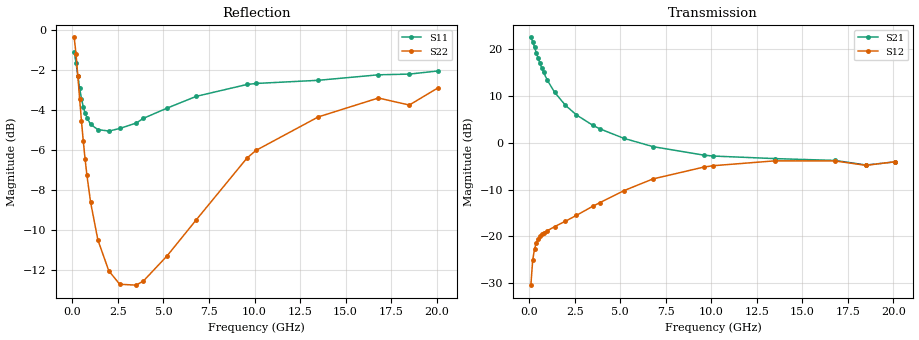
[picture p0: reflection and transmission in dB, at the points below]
!  Infineon Technologies AG
! BFR380L3 , PF131585-7, No.6, Th 09.10.01, soldered on pcb-board, measured with PP GSG850
!  Vce=2.0 V,  Ic=4.0 mA
! Common Emitter S-Parameters:  15. November 2001
#  GHz  S  MA  R  50
! f  S11  S21  S12  S22
! GHz  Mag  Ang  Mag  Ang  Mag  Ang  Mag  Ang
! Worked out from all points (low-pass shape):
!   201 points, 100 MHz to 20.1 GHz, reference 50 ohm
!   highest |S21| = 22.46 dB at 100 MHz (marker M1); lowest = -4.8 dB at 18.5 GHz (marker M2)
!   |S21| within 3 dB of the highest: start of sweep to 378.5 MHz
!   lowest |S11| = -5.1 dB at 2 GHz (marker M3), VSWR 3.53, Z = 14.2 + j0.206 ohm
!   |S11| at or under -10 dB: nowhere
!   |S22| runs from -12.9 to -0.4 dB; largest |S21 - S12| = 13
!   S11 on the Smith chart (normalised r, x): 100 MHz: 1.14, -3.99; 400 MHz: 0.34, -1.00; 1 GHz: 0.29, -0.31; 3.9 GHz: 0.28, +0.32; 9.6 GHz: 0.36, +1.11; 20.1 GHz: 0.98, +2.55
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0.1  0.8814 -26.2  13.27 162.5  0.03022 75.1  0.9583 -15.7
0.2  0.8274 -49.6  11.92 147.4  0.05574 64.3  0.8697 -29.3
0.3  0.7691 -70.4  10.47 135.0  0.0735 55.5  0.7655 -39.9
0.4  0.7137 -86.6  9.117 125.2  0.08551 49.1  0.6703 -47.9
0.5  0.6729 -100.4  7.968 117.4  0.09385 44.9  0.5908 -54.0
0.6  0.6416 -111.8  7.012 111.1  0.1001 42.1  0.5263 -58.7
0.7  0.6183 -121.5  6.247 105.7  0.1048 40.0  0.4742 -62.5
0.8  0.6036 -129.4  5.607 101.2  0.1088 38.9  0.4323 -65.6
1  0.5801 -142.7  4.65 93.7  0.1151 37.8  0.3705 -70.4
1.4  0.5632 -161.6  3.452 82.2  0.1268 38.5  0.298 -77.8
2  0.5584 179.5  2.499 69.1  0.1453 41.7  0.2494 -87.4
2.6  0.5667 165.3  1.979 58.2  0.1676 44.8  0.2308 -97.7
3.5  0.5846 148.4  1.531 44.3  0.2097 47.5  0.2297 -113.7
3.9  0.6009 142.2  1.402 39.0  0.2296 47.8  0.2352 -122.4
5.2  0.6373 124.0  1.113 23.8  0.307 44.5  0.2719 -147.1
6.8  0.6821 104.8  0.9073 10.0  0.4101 36.6  0.3346 -177.3
9.6  0.7307 80.7  0.7359 -5.2  0.5489 17.4  0.4787 142.6
10.1  0.7348 77.2  0.7197 -7.2  0.5675 13.7  0.5 136.3
13.5  0.7482 59.2  0.6759 -20.6  0.6396 -9.0  0.6058 102.1
16.8  0.7723 47.3  0.6464 -32.1  0.6383 -25.7  0.6756 78.4
18.5  0.7755 45.5  0.5773 -39.7  0.5729 -34.3  0.6488 72.3
20.1  0.7899 38.4  0.6237 -43.5  0.626 -39.4  0.7174 61.3
